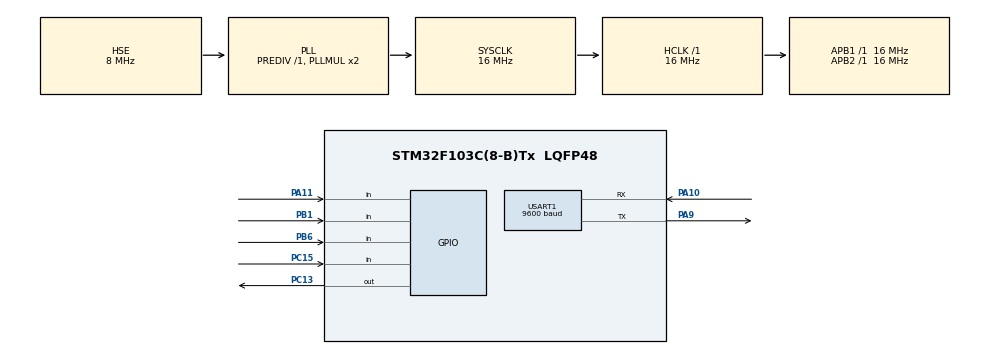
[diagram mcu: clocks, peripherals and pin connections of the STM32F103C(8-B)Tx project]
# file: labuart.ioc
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Mcu.Family=STM32F1
Mcu.Name=STM32F103C(8-B)Tx
Mcu.Package=LQFP48
NVIC.PriorityGroup=NVIC_PRIORITYGROUP_4
NVIC.TIM3_IRQn=true\:0\:0\:false\:false\:true\:true
PA10.Mode=Asynchronous
PA10.Signal=USART1_RX
PA11.GPIO_PuPd=GPIO_PULLDOWN
PA11.Signal=GPIO_Input
PA9.Mode=Asynchronous
PA9.Signal=USART1_TX
PB1.GPIO_PuPd=GPIO_PULLDOWN
PB1.Signal=GPIO_Input
PB6.GPIO_PuPd=GPIO_PULLUP
PB6.Signal=GPIO_Input
PC13-TAMPER-RTC.Signal=GPIO_Output
PC15-OSC32_OUT.GPIO_PuPd=GPIO_PULLDOWN
PC15-OSC32_OUT.Signal=GPIO_Input
PD0-OSC_IN.Mode=HSE-External-Oscillator
PD0-OSC_IN.Signal=RCC_OSC_IN
PD1-OSC_OUT.Mode=HSE-External-Oscillator
PD1-OSC_OUT.Signal=RCC_OSC_OUT
ProjectManager.HeapSize=0x200
ProjectManager.StackSize=0x400
ProjectManager.TargetToolchain=EWARM
RCC.AHBFreq_Value=16000000
RCC.APB1Freq_Value=16000000
RCC.APB1TimFreq_Value=16000000
RCC.APB2Freq_Value=16000000
RCC.APB2TimFreq_Value=16000000
RCC.HCLKFreq_Value=16000000
RCC.PLLSourceVirtual=RCC_PLLSOURCE_HSE
RCC.SYSCLKFreq_VALUE=16000000
RCC.SYSCLKSource=RCC_SYSCLKSOURCE_PLLCLK
RCC.USBFreq_Value=16000000
TIM3.ClockDivision=TIM_CLOCKDIVISION_DIV2
TIM3.Period=500
TIM3.Prescaler=36000
USART1.BaudRate=9600
USART1.VirtualMode=VM_ASYNC
VP_SYS_VS_ND.Mode=No_Debug
VP_TIM3_VS_ClockSourceINT.Mode=Internal
board=labuart

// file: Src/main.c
/**
  ******************************************************************************
  * File Name          : main.c
  * Description        : Main program body
  ******************************************************************************
  ** This notice applies to any and all portions of this file
  * that are not between comment pairs USER CODE BEGIN and
  * USER CODE END. Other portions of this file, whether
  * inserted by the user or by software development tools
  * are owned by their respective copyright owners.
  *
  * COPYRIGHT(c) 2018 STMicroelectronics
  *
  * Redistribution and use in source and binary forms, with or without modification,
  * are permitted provided that the following conditions are met:
  *   1. Redistributions of source code must retain the above copyright notice,
  *      this list of conditions and the following disclaimer.
  *   2. Redistributions in binary form must reproduce the above copyright notice,
  *      this list of conditions and the following disclaimer in the documentation
  *      and/or other materials provided with the distribution.
  *   3. Neither the name of STMicroelectronics nor the names of its contributors
  *      may be used to endorse or promote products derived from this software
  *      without specific prior written permission.
  *
  * THIS SOFTWARE IS PROVIDED BY THE COPYRIGHT HOLDERS AND CONTRIBUTORS "AS IS"
  * AND ANY EXPRESS OR IMPLIED WARRANTIES, INCLUDING, BUT NOT LIMITED TO, THE
  * IMPLIED WARRANTIES OF MERCHANTABILITY AND FITNESS FOR A PARTICULAR PURPOSE ARE
  * DISCLAIMED. IN NO EVENT SHALL THE COPYRIGHT HOLDER OR CONTRIBUTORS BE LIABLE
  * FOR ANY DIRECT, INDIRECT, INCIDENTAL, SPECIAL, EXEMPLARY, OR CONSEQUENTIAL
  * DAMAGES (INCLUDING, BUT NOT LIMITED TO, PROCUREMENT OF SUBSTITUTE GOODS OR
  * SERVICES; LOSS OF USE, DATA, OR PROFITS; OR BUSINESS INTERRUPTION) HOWEVER
  * CAUSED AND ON ANY THEORY OF LIABILITY, WHETHER IN CONTRACT, STRICT LIABILITY,
  * OR TORT (INCLUDING NEGLIGENCE OR OTHERWISE) ARISING IN ANY WAY OUT OF THE USE
  * OF THIS SOFTWARE, EVEN IF ADVISED OF THE POSSIBILITY OF SUCH DAMAGE.
  *
  ******************************************************************************
  */

#include "main.h"
#include "stm32f1xx_hal.h"

TIM_HandleTypeDef htim3;

UART_HandleTypeDef huart1;

/* USER CODE BEGIN PV */
/* Private variables ---------------------------------------------------------*/

/* USER CODE END PV */

void SystemClock_Config(void);
static void MX_GPIO_Init(void);
static void MX_TIM3_Init(void);
static void MX_USART1_UART_Init(void);

/* USER CODE BEGIN PFP */
/* Private function prototypes -----------------------------------------------*/

/* USER CODE END PFP */

int main(void)
{

  /* MCU Configuration----------------------------------------------------------*/

  /* Reset of all peripherals, Initializes the Flash interface and the Systick. */
  HAL_Init();

  /* Configure the system clock */
  SystemClock_Config();

  /* Initialize all configured peripherals */
  MX_GPIO_Init();
  MX_TIM3_Init();
  MX_USART1_UART_Init();

  /* USER CODE BEGIN 2 */
  uint8_t str[] = "Hello UART\r\n";
  /* USER CODE END 2 */

  /* Infinite loop */
  while (1)
  {

  /* USER CODE BEGIN 3 */
	  HAL_UART_Transmit(&huart1, str, sizeof(str) - 1, HAL_MAX_DELAY);
	  HAL_Delay(1000);

  }
  /* USER CODE END 3 */

}
void send_str(char *str)
{
	while (str !=0)
	{
		HAL_UART_Transmit (&huart1, (uint8_t *)str, 1, HAL_MAX_DELAY);
		str++;
	}
}

/** System Clock Configuration
*/
void SystemClock_Config(void)
{

  RCC_OscInitTypeDef RCC_OscInitStruct;
  RCC_ClkInitTypeDef RCC_ClkInitStruct;

    /**Initializes the CPU, AHB and APB busses clocks
    */
  RCC_OscInitStruct.OscillatorType = RCC_OSCILLATORTYPE_HSE;
  RCC_OscInitStruct.HSEState = RCC_HSE_ON;
  RCC_OscInitStruct.HSEPredivValue = RCC_HSE_PREDIV_DIV1;
  RCC_OscInitStruct.HSIState = RCC_HSI_ON;
  RCC_OscInitStruct.PLL.PLLState = RCC_PLL_ON;
  RCC_OscInitStruct.PLL.PLLSource = RCC_PLLSOURCE_HSE;
  RCC_OscInitStruct.PLL.PLLMUL = RCC_PLL_MUL2;
  if (HAL_RCC_OscConfig(&RCC_OscInitStruct) != HAL_OK)
  {
    _Error_Handler(__FILE__, __LINE__);
  }

    /**Initializes the CPU, AHB and APB busses clocks
    */
  RCC_ClkInitStruct.ClockType = RCC_CLOCKTYPE_HCLK|RCC_CLOCKTYPE_SYSCLK
                              |RCC_CLOCKTYPE_PCLK1|RCC_CLOCKTYPE_PCLK2;
  RCC_ClkInitStruct.SYSCLKSource = RCC_SYSCLKSOURCE_PLLCLK;
  RCC_ClkInitStruct.AHBCLKDivider = RCC_SYSCLK_DIV1;
  RCC_ClkInitStruct.APB1CLKDivider = RCC_HCLK_DIV1;
  RCC_ClkInitStruct.APB2CLKDivider = RCC_HCLK_DIV1;

  if (HAL_RCC_ClockConfig(&RCC_ClkInitStruct, FLASH_LATENCY_0) != HAL_OK)
  {
    _Error_Handler(__FILE__, __LINE__);
  }

    /**Configure the Systick interrupt time
    */
  HAL_SYSTICK_Config(HAL_RCC_GetHCLKFreq()/1000);

    /**Configure the Systick
    */
  HAL_SYSTICK_CLKSourceConfig(SYSTICK_CLKSOURCE_HCLK);

  /* SysTick_IRQn interrupt configuration */
  HAL_NVIC_SetPriority(SysTick_IRQn, 0, 0);
}

/* TIM3 init function */
static void MX_TIM3_Init(void)
{

  TIM_ClockConfigTypeDef sClockSourceConfig;
  TIM_MasterConfigTypeDef sMasterConfig;

  htim3.Instance = TIM3;
  htim3.Init.Prescaler = 36000;
  htim3.Init.CounterMode = TIM_COUNTERMODE_UP;
  htim3.Init.Period = 500;
  htim3.Init.ClockDivision = TIM_CLOCKDIVISION_DIV2;
  htim3.Init.AutoReloadPreload = TIM_AUTORELOAD_PRELOAD_DISABLE;
  if (HAL_TIM_Base_Init(&htim3) != HAL_OK)
  {
    _Error_Handler(__FILE__, __LINE__);
  }

  sClockSourceConfig.ClockSource = TIM_CLOCKSOURCE_INTERNAL;
  if (HAL_TIM_ConfigClockSource(&htim3, &sClockSourceConfig) != HAL_OK)
  {
    _Error_Handler(__FILE__, __LINE__);
  }

  sMasterConfig.MasterOutputTrigger = TIM_TRGO_RESET;
  sMasterConfig.MasterSlaveMode = TIM_MASTERSLAVEMODE_DISABLE;
  if (HAL_TIMEx_MasterConfigSynchronization(&htim3, &sMasterConfig) != HAL_OK)
  {
    _Error_Handler(__FILE__, __LINE__);
  }

}

/* USART1 init function */
static void MX_USART1_UART_Init(void)
{

  huart1.Instance = USART1;
  huart1.Init.BaudRate = 9600;
  huart1.Init.WordLength = UART_WORDLENGTH_8B;
  huart1.Init.StopBits = UART_STOPBITS_1;
  huart1.Init.Parity = UART_PARITY_NONE;
  huart1.Init.Mode = UART_MODE_TX_RX;
  huart1.Init.HwFlowCtl = UART_HWCONTROL_NONE;
  huart1.Init.OverSampling = UART_OVERSAMPLING_16;
  if (HAL_UART_Init(&huart1) != HAL_OK)
  {
    _Error_Handler(__FILE__, __LINE__);
  }

}

/** Configure pins as
        * Analog
        * Input
        * Output
        * EVENT_OUT
        * EXTI
        * Free pins are configured automatically as Analog (this feature is enabled through
        * the Code Generation settings)
*/
static void MX_GPIO_Init(void)
{

  GPIO_InitTypeDef GPIO_InitStruct;

  /* GPIO Ports Clock Enable */
  __HAL_RCC_GPIOC_CLK_ENABLE();
  __HAL_RCC_GPIOD_CLK_ENABLE();
  __HAL_RCC_GPIOA_CLK_ENABLE();
  __HAL_RCC_GPIOB_CLK_ENABLE();

  /*Configure GPIO pin Output Level */
  HAL_GPIO_WritePin(GPIOC, GPIO_PIN_13, GPIO_PIN_RESET);

  /*Configure GPIO pin : PC13 */
  GPIO_InitStruct.Pin = GPIO_PIN_13;
  GPIO_InitStruct.Mode = GPIO_MODE_OUTPUT_PP;
  GPIO_InitStruct.Speed = GPIO_SPEED_FREQ_LOW;
  HAL_GPIO_Init(GPIOC, &GPIO_InitStruct);

  /*Configure GPIO pins : PC14 PC15 */
  GPIO_InitStruct.Pin = GPIO_PIN_14|GPIO_PIN_15;
  GPIO_InitStruct.Mode = GPIO_MODE_ANALOG;
  HAL_GPIO_Init(GPIOC, &GPIO_InitStruct);

  /*Configure GPIO pins : PA0 PA1 PA2 PA3
                           PA4 PA5 PA6 PA7
                           PA8 PA11 PA12 PA15 */
  GPIO_InitStruct.Pin = GPIO_PIN_0|GPIO_PIN_1|GPIO_PIN_2|GPIO_PIN_3
                          |GPIO_PIN_4|GPIO_PIN_5|GPIO_PIN_6|GPIO_PIN_7
                          |GPIO_PIN_8|GPIO_PIN_11|GPIO_PIN_12|GPIO_PIN_15;
  GPIO_InitStruct.Mode = GPIO_MODE_ANALOG;
  HAL_GPIO_Init(GPIOA, &GPIO_InitStruct);

  /*Configure GPIO pins : PB0 PB1 PB2 PB11
                           PB13 PB15 PB3 PB4
                           PB5 PB7 PB8 PB9 */
  GPIO_InitStruct.Pin = GPIO_PIN_0|GPIO_PIN_1|GPIO_PIN_2|GPIO_PIN_11
                          |GPIO_PIN_13|GPIO_PIN_15|GPIO_PIN_3|GPIO_PIN_4
                          |GPIO_PIN_5|GPIO_PIN_7|GPIO_PIN_8|GPIO_PIN_9;
  GPIO_InitStruct.Mode = GPIO_MODE_ANALOG;
  HAL_GPIO_Init(GPIOB, &GPIO_InitStruct);

  /*Configure GPIO pins : PB10 PB12 PB14 */
  GPIO_InitStruct.Pin = GPIO_PIN_10|GPIO_PIN_12|GPIO_PIN_14;
  GPIO_InitStruct.Mode = GPIO_MODE_INPUT;
  GPIO_InitStruct.Pull = GPIO_PULLDOWN;
  HAL_GPIO_Init(GPIOB, &GPIO_InitStruct);

  /*Configure GPIO pin : PB6 */
  GPIO_InitStruct.Pin = GPIO_PIN_6;
  GPIO_InitStruct.Mode = GPIO_MODE_INPUT;
  GPIO_InitStruct.Pull = GPIO_PULLUP;
  HAL_GPIO_Init(GPIOB, &GPIO_InitStruct);

}

/* USER CODE BEGIN 4 */
/*void HAL_UART_RxCpltCallback(UART_Handletype)
{
if (huart ==&huart1){
	}
else if (huart == &huart2){
}
}

}*/
/* USER CODE END 4 */

void _Error_Handler(char * file, int line)
{
  while(1)
  {
  }
}

/************************ (C) COPYRIGHT STMicroelectronics *****END OF FILE****/
